VERSION 5.7 ;
  NOWIREEXTENSIONATPIN ON ;
  DIVIDERCHAR "/" ;
  BUSBITCHARS "[]" ;
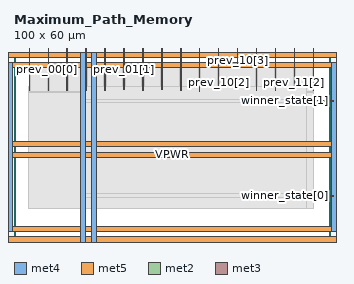
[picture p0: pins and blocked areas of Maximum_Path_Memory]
MACRO Maximum_Path_Memory
  CLASS BLOCK ;
  FOREIGN Maximum_Path_Memory ;
  ORIGIN 0.000 0.000 ;
  SIZE 100.000 BY 60.000 ;
  PIN VGND
    DIRECTION INOUT ;
    USE GROUND ;
    PORT
      LAYER met4 ;
        RECT -5.380 -0.020 -3.780 59.860 ;
    END
    PORT
      LAYER met5 ;
        RECT -5.380 -0.020 105.200 1.580 ;
    END
    PORT
      LAYER met5 ;
        RECT -5.380 58.260 105.200 59.860 ;
    END
    PORT
      LAYER met4 ;
        RECT 103.600 -0.020 105.200 59.860 ;
    END
    PORT
      LAYER met4 ;
        RECT 24.340 -0.020 25.940 59.860 ;
    END
    PORT
      LAYER met5 ;
        RECT -5.380 30.030 105.200 31.630 ;
    END
  END VGND
  PIN VPWR
    DIRECTION INOUT ;
    USE POWER ;
    PORT
      LAYER met4 ;
        RECT -2.080 3.280 -0.480 56.560 ;
    END
    PORT
      LAYER met5 ;
        RECT -2.080 3.280 101.900 4.880 ;
    END
    PORT
      LAYER met5 ;
        RECT -2.080 54.960 101.900 56.560 ;
    END
    PORT
      LAYER met4 ;
        RECT 100.300 3.280 101.900 56.560 ;
    END
    PORT
      LAYER met4 ;
        RECT 21.040 -0.020 22.640 59.860 ;
    END
    PORT
      LAYER met5 ;
        RECT -5.380 26.730 105.200 28.330 ;
    END
  END VPWR
  PIN prev_00[0]
    DIRECTION INPUT ;
    USE SIGNAL ;
    ANTENNAGATEAREA 0.196500 ;
    PORT
      LAYER met2 ;
        RECT 4.760 47.900 4.900 61.000 ;
    END
  END prev_00[0]
  PIN prev_00[1]
    DIRECTION INPUT ;
    USE SIGNAL ;
    ANTENNAGATEAREA 0.196500 ;
    PORT
      LAYER met2 ;
        RECT 10.740 47.900 10.880 61.000 ;
    END
  END prev_00[1]
  PIN prev_00[2]
    DIRECTION INPUT ;
    USE SIGNAL ;
    ANTENNAGATEAREA 0.196500 ;
    PORT
      LAYER met2 ;
        RECT 16.720 47.900 16.860 61.000 ;
    END
  END prev_00[2]
  PIN prev_00[3]
    DIRECTION INPUT ;
    USE SIGNAL ;
    ANTENNAGATEAREA 0.196500 ;
    PORT
      LAYER met2 ;
        RECT 22.700 47.900 22.840 61.000 ;
    END
  END prev_00[3]
  PIN prev_01[0]
    DIRECTION INPUT ;
    USE SIGNAL ;
    ANTENNAGATEAREA 0.196500 ;
    PORT
      LAYER met2 ;
        RECT 28.680 47.900 28.820 61.000 ;
    END
  END prev_01[0]
  PIN prev_01[1]
    DIRECTION INPUT ;
    USE SIGNAL ;
    ANTENNAGATEAREA 0.196500 ;
    PORT
      LAYER met2 ;
        RECT 34.660 48.240 34.800 61.000 ;
    END
  END prev_01[1]
  PIN prev_01[2]
    DIRECTION INPUT ;
    USE SIGNAL ;
    ANTENNAGATEAREA 0.196500 ;
    PORT
      LAYER met2 ;
        RECT 40.640 47.900 40.780 61.000 ;
    END
  END prev_01[2]
  PIN prev_01[3]
    DIRECTION INPUT ;
    USE SIGNAL ;
    ANTENNAGATEAREA 0.196500 ;
    PORT
      LAYER met2 ;
        RECT 46.620 48.040 46.760 61.000 ;
    END
  END prev_01[3]
  PIN prev_10[0]
    DIRECTION INPUT ;
    USE SIGNAL ;
    ANTENNAGATEAREA 0.196500 ;
    PORT
      LAYER met2 ;
        RECT 52.600 47.900 52.740 61.000 ;
    END
  END prev_10[0]
  PIN prev_10[1]
    DIRECTION INPUT ;
    USE SIGNAL ;
    ANTENNAGATEAREA 0.196500 ;
    PORT
      LAYER met2 ;
        RECT 58.580 47.560 58.720 61.000 ;
    END
  END prev_10[1]
  PIN prev_10[2]
    DIRECTION INPUT ;
    USE SIGNAL ;
    ANTENNAGATEAREA 0.196500 ;
    PORT
      LAYER met2 ;
        RECT 64.560 47.900 64.700 61.000 ;
    END
  END prev_10[2]
  PIN prev_10[3]
    DIRECTION INPUT ;
    USE SIGNAL ;
    ANTENNAGATEAREA 0.196500 ;
    PORT
      LAYER met2 ;
        RECT 70.540 55.350 70.680 61.000 ;
    END
  END prev_10[3]
  PIN prev_11[0]
    DIRECTION INPUT ;
    USE SIGNAL ;
    ANTENNAGATEAREA 0.196500 ;
    PORT
      LAYER met2 ;
        RECT 76.520 47.900 76.660 61.000 ;
    END
  END prev_11[0]
  PIN prev_11[1]
    DIRECTION INPUT ;
    USE SIGNAL ;
    ANTENNAGATEAREA 0.196500 ;
    PORT
      LAYER met2 ;
        RECT 82.500 47.900 82.640 61.000 ;
    END
  END prev_11[1]
  PIN prev_11[2]
    DIRECTION INPUT ;
    USE SIGNAL ;
    ANTENNAGATEAREA 0.196500 ;
    PORT
      LAYER met2 ;
        RECT 88.480 47.900 88.620 61.000 ;
    END
  END prev_11[2]
  PIN prev_11[3]
    DIRECTION INPUT ;
    USE SIGNAL ;
    ANTENNAGATEAREA 0.196500 ;
    PORT
      LAYER met2 ;
        RECT 94.460 47.900 94.600 61.000 ;
    END
  END prev_11[3]
  PIN winner_state[0]
    DIRECTION OUTPUT ;
    USE SIGNAL ;
    ANTENNADIFFAREA 0.445500 ;
    PORT
      LAYER met3 ;
        RECT 92.370 14.470 101.000 14.770 ;
    END
  END winner_state[0]
  PIN winner_state[1]
    DIRECTION OUTPUT ;
    USE SIGNAL ;
    ANTENNADIFFAREA 0.445500 ;
    PORT
      LAYER met3 ;
        RECT 92.370 44.390 101.000 44.690 ;
    END
  END winner_state[1]
  OBS
      LAYER nwell ;
        RECT 5.330 10.795 94.490 49.045 ;
      LAYER li1 ;
        RECT 5.520 10.795 94.300 49.045 ;
      LAYER met1 ;
        RECT 4.670 10.640 94.690 49.200 ;
      LAYER met2 ;
        RECT 5.180 47.620 10.460 56.170 ;
        RECT 11.160 47.620 16.440 56.170 ;
        RECT 17.140 47.620 22.420 56.170 ;
        RECT 23.120 47.620 28.400 56.170 ;
        RECT 29.100 47.960 34.380 56.170 ;
        RECT 35.080 47.960 40.360 56.170 ;
        RECT 29.100 47.620 40.360 47.960 ;
        RECT 41.060 47.760 46.340 56.170 ;
        RECT 47.040 47.760 52.320 56.170 ;
        RECT 41.060 47.620 52.320 47.760 ;
        RECT 53.020 47.620 58.300 56.170 ;
        RECT 4.700 47.280 58.300 47.620 ;
        RECT 59.000 47.620 64.280 56.170 ;
        RECT 64.980 55.070 70.260 56.170 ;
        RECT 70.960 55.070 76.240 56.170 ;
        RECT 64.980 47.620 76.240 55.070 ;
        RECT 76.940 47.620 82.220 56.170 ;
        RECT 82.920 47.620 88.200 56.170 ;
        RECT 88.900 47.620 94.180 56.170 ;
        RECT 59.000 47.280 94.660 47.620 ;
        RECT 4.700 10.695 94.660 47.280 ;
      LAYER met3 ;
        RECT 21.050 45.090 92.395 49.125 ;
        RECT 21.050 43.990 91.970 45.090 ;
        RECT 21.050 15.170 92.395 43.990 ;
        RECT 21.050 14.070 91.970 15.170 ;
        RECT 21.050 10.715 92.395 14.070 ;
  END
END Maximum_Path_Memory
END LIBRARY

